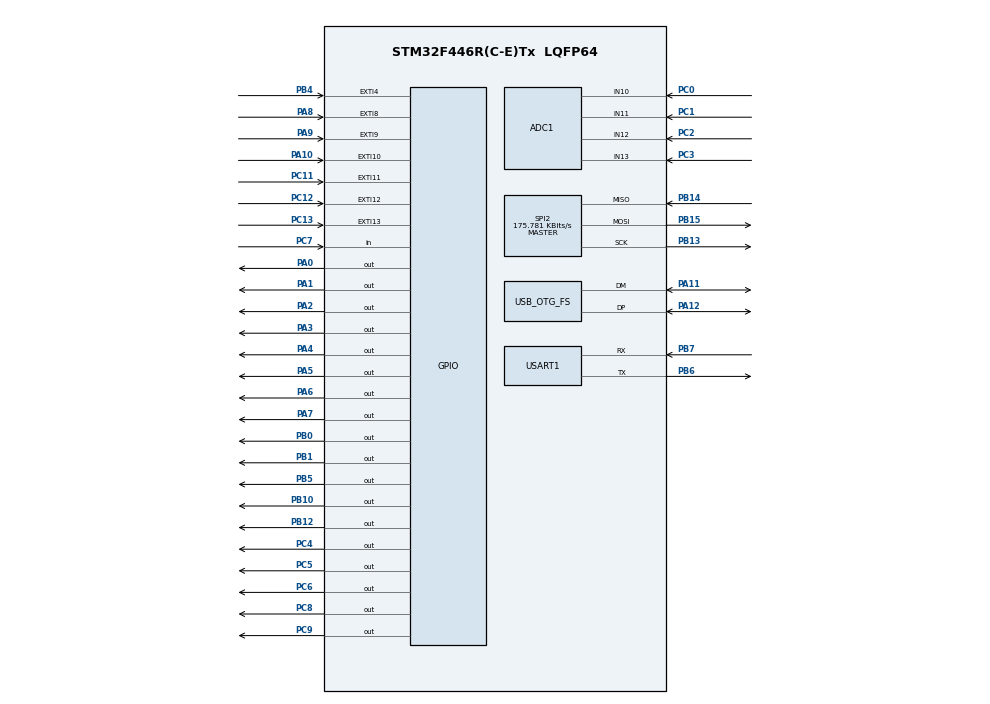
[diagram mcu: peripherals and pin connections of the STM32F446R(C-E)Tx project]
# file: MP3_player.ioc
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ADC1.Channel-0\#ChannelRegularConversion=ADC_CHANNEL_10
ADC1.NbrOfConversionFlag=1
ADC1.Rank-0\#ChannelRegularConversion=1
ADC1.SamplingTime-0\#ChannelRegularConversion=ADC_SAMPLETIME_3CYCLES
ADC1.master=1
FATFS._USE_FIND=1
FATFS._USE_LFN=2
FREERTOS.Tasks01=ControlTask,24,128,StartControlTask,Default,NULL,Dynamic,NULL,NULL;AudioTask,8,512,StartAudioTask,Default,NULL,Dynamic,NULL,NULL
FREERTOS.configUSE_NEWLIB_REENTRANT=1
Mcu.Family=STM32F4
Mcu.Name=STM32F446R(C-E)Tx
Mcu.Package=LQFP64
NVIC.EXTI15_10_IRQn=true\:5\:0\:false\:false\:true\:true\:true\:true\:true
NVIC.EXTI4_IRQn=true\:5\:0\:false\:false\:true\:true\:true\:true\:true
NVIC.EXTI9_5_IRQn=true\:5\:0\:false\:false\:true\:true\:true\:true\:true
NVIC.PriorityGroup=NVIC_PRIORITYGROUP_4
NVIC.TIM6_DAC_IRQn=true\:15\:0\:false\:false\:true\:false\:false\:true\:true
NVIC.TimeBase=TIM6_DAC_IRQn
NVIC.TimeBaseIP=TIM6
PA0-WKUP.Signal=GPIO_Output
PA1.Signal=GPIO_Output
PA10.Signal=GPXTI10
PA11.Mode=Device_Only
PA11.Signal=USB_OTG_FS_DM
PA12.Mode=Device_Only
PA12.Signal=USB_OTG_FS_DP
PA13.Mode=Serial_Wire
PA13.Signal=SYS_JTMS-SWDIO
PA14.Mode=Serial_Wire
PA14.Signal=SYS_JTCK-SWCLK
PA2.Signal=GPIO_Output
PA3.Signal=GPIO_Output
PA4.Signal=GPIO_Output
PA5.Signal=GPIO_Output
PA6.Signal=GPIO_Output
PA7.Signal=GPIO_Output
PA8.Signal=GPXTI8
PA9.Signal=GPXTI9
PB0.Signal=GPIO_Output
PB1.Signal=GPIO_Output
PB10.Signal=GPIO_Output
PB12.Signal=GPIO_Output
PB13.Mode=Full_Duplex_Master
PB13.Signal=SPI2_SCK
PB14.Mode=Full_Duplex_Master
PB14.Signal=SPI2_MISO
PB15.Mode=Full_Duplex_Master
PB15.Signal=SPI2_MOSI
PB4.Signal=GPXTI4
PB5.Signal=GPIO_Output
PB6.Mode=Asynchronous
PB6.Signal=USART1_TX
PB7.Mode=Asynchronous
PB7.Signal=USART1_RX
PC0.Signal=ADCx_IN10
PC1.Signal=ADCx_IN11
PC11.Signal=GPXTI11
PC12.Signal=GPXTI12
PC13.Signal=GPXTI13
PC14-OSC32_IN.Mode=LSE-External-Oscillator
PC14-OSC32_IN.Signal=RCC_OSC32_IN
PC15-OSC32_OUT.Mode=LSE-External-Oscillator
PC15-OSC32_OUT.Signal=RCC_OSC32_OUT
PC2.Signal=ADCx_IN12
PC3.Signal=ADCx_IN13
PC4.Signal=GPIO_Output
PC5.Signal=GPIO_Output
PC6.Signal=GPIO_Output
PC7.Signal=GPIO_Input
PC8.Signal=GPIO_Output
PC9.Signal=GPIO_Output
PH0-OSC_IN.Mode=HSE-External-Oscillator
PH0-OSC_IN.Signal=RCC_OSC_IN
PH1-OSC_OUT.Mode=HSE-External-Oscillator
PH1-OSC_OUT.Signal=RCC_OSC_OUT
ProjectManager.HeapSize=0x200
ProjectManager.StackSize=0x400
ProjectManager.TargetToolchain=STM32CubeIDE
RCC.AHBFreq_Value=90000000
RCC.APB1CLKDivider=RCC_HCLK_DIV2
RCC.APB1Freq_Value=45000000
RCC.APB1TimFreq_Value=90000000
RCC.APB2Freq_Value=90000000
RCC.APB2TimFreq_Value=90000000
RCC.CortexFreq_Value=90000000
RCC.HCLKFreq_Value=90000000
RCC.HSE_VALUE=8000000
RCC.PLLM=8
RCC.PLLN=360
RCC.PLLP=RCC_PLLP_DIV4
RCC.PLLSAIM=8
RCC.PLLSAIP=RCC_PLLSAIP_DIV4
RCC.PLLSourceVirtual=RCC_PLLSOURCE_HSE
RCC.SYSCLKFreq_VALUE=90000000
RCC.SYSCLKSource=RCC_SYSCLKSOURCE_PLLCLK
RCC.USBCLockSelection=RCC_CLK48CLKSOURCE_PLLSAIP
RCC.USBFreq_Value=48000000
RCC.VCOOutputFreq_Value=360000000
SH.ADCx_IN10.0=ADC1_IN10,IN10
SH.ADCx_IN11.0=ADC1_IN11,IN11
SH.ADCx_IN12.0=ADC1_IN12,IN12
SH.ADCx_IN13.0=ADC1_IN13,IN13
SPI2.BaudRatePrescaler=SPI_BAUDRATEPRESCALER_256
SPI2.CalculateBaudRate=175.781 KBits/s
SPI2.Direction=SPI_DIRECTION_2LINES
SPI2.Mode=SPI_MODE_MASTER
SPI2.VirtualType=VM_MASTER
USART1.VirtualMode=VM_ASYNC
USB_OTG_FS.VirtualMode=Device_Only
VP_FATFS_VS_Generic.Mode=User_defined
VP_FREERTOS_VS_CMSIS_V2.Mode=CMSIS_V2
VP_SYS_VS_tim6.Mode=TIM6
board=custom

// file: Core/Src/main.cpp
/* USER CODE BEGIN Header */
/**
 ******************************************************************************
 * @file           : main.c
 * @brief          : Main program body
 ******************************************************************************
 * @attention
 *
 * Copyright (c) 2025 STMicroelectronics.
 * All rights reserved.
 *
 * This software is licensed under terms that can be found in the LICENSE file
 * in the root directory of this software component.
 * If no LICENSE file comes with this software, it is provided AS-IS.
 *
 ******************************************************************************
 */
/* USER CODE END Header */
#include "main.h"
#include <cstdio>
#include <iostream>

#include "cmsis_os.h"
#include "fatfs.h"
//#include "lvgl.h"

#include "myfunc.h"
#include "MP3.h"
#include "Bitmap.h"

#include "TFT_LCD.h"
#include "SDcard.h"
#include "VS1003B.h"

using namespace std;

ADC_HandleTypeDef hadc1;

SPI_HandleTypeDef hspi2;

UART_HandleTypeDef huart1;

PCD_HandleTypeDef hpcd_USB_OTG_FS;

/* Definitions for ControlTask */
osThreadId_t ControlTaskHandle;
const osThreadAttr_t ControlTask_attributes = { .name = "ControlTask",
		.stack_size = 1024 * 4, .priority = (osPriority_t) osPriorityNormal, };
/* Definitions for AudioTask */
osThreadId_t AudioTaskHandle;
const osThreadAttr_t AudioTask_attributes = { .name = "AudioTask", .stack_size =
		1024 * 4, .priority = (osPriority_t) osPriorityLow, };

osSemaphoreId_t stateSemaphore;
osMessageQueueId_t buttonQueue;

/*class UARTRedirector: public std::streambuf {
protected:
	int overflow(int c) override {
		if (c != EOF) {
			HAL_UART_Transmit(&huart1, (uint8_t*) &c, 1, HAL_MAX_DELAY);
		}
		return c;
	}
};*/
class UARTRedirector : public std::streambuf {
private:
  char buffer[128];
  int pos = 0;
protected:
  int overflow(int c) override {
    if (c != EOF) {
      buffer[pos++] = (char)c;
      if (pos >= sizeof(buffer) || c == '\n') {
        HAL_UART_Transmit(&huart1, (uint8_t*)buffer, pos, 10);
        pos = 0;
      }
    }
    return c;
  }
  int sync() override {
    if (pos > 0) {
      HAL_UART_Transmit(&huart1, (uint8_t*)buffer, pos, 10);
      pos = 0;
    }
    return 0;
  }
};

UARTRedirector uart_redirector;

void SystemClock_Config(void);
static void MX_GPIO_Init(void);
static void MX_ADC1_Init(void);
static void MX_SPI2_Init(void);
static void MX_USART1_UART_Init(void);
static void MX_USB_OTG_FS_PCD_Init(void);
void StartControlTask(void *argument);
void StartAudioTask(void *argument);

void Home_page();
static void Main_page();
static void init_page();
void UpdateMusicName(char* name);
void FolderListPage(TCHAR* PATH);

/* USER CODE BEGIN 0 */

TFT_LCD &lcd = TFT_LCD::getInstance();
SDcard &sd = SDcard::getInstance();
VS1003B &vs = VS1003B::getInstance();
char PATH[256]="/";
int current_page=HOME_PAGE;
bool botton_next = 0;
bool botton_prev = 0;
bool botton_repeat = 0;
bool botton_pause = 0;
bool init=0;
volatile bool is_playing = 0;
bool reset_track = 1;
volatile int numofFile = 0;
int music_no = 0;
uint8_t volume=200;
int FolderCount=0;
int folders=0;
uint8_t folder_idx=0;
#define SIZE 100

uint16_t play_emoji[SIZE * SIZE];
uint16_t pause_emoji[SIZE * SIZE];
//uint16_t next_emoji[SIZE * SIZE];
uint16_t prev_emoji[SIZE * SIZE];
uint16_t repeat[3200];
uint16_t repeat1[3200];

extern FATFS fs;           // File system object
extern FIL fil;            // File object
extern FILINFO fno;        // File information object
extern DIR dir;            // Directory object
extern TCHAR fileNames[MAX_FILES][MAX_FILENAME];  // 파일 이름 저장 배열
extern TCHAR FolderNames[MAX_FILES][MAX_FILENAME];
extern volatile UINT fileCount; // 파일 개수

/* USER CODE END 0 */

int main(void) {

	/* MCU Configuration--------------------------------------------------------*/

	/* Reset of all peripherals, Initializes the Flash interface and the Systick. */
	HAL_Init();

	/* Configure the system clock */
	SystemClock_Config();

	/* Initialize all configured peripherals */
	MX_GPIO_Init();
	MX_ADC1_Init();
	MX_SPI2_Init();
	MX_USART1_UART_Init();
	//MX_USB_OTG_FS_PCD_Init();
	MX_FATFS_Init();
	std::cout.rdbuf(&uart_redirector);
	/* USER CODE BEGIN 2 */
	//init_page();
	//cout<<"music start\r"<<endl;
	//MP3_Play(0);
	//cout<<"kernel start\r"<<endl;
	/* USER CODE END 2 */

	/* Init scheduler */
	osKernelInitialize();

	/* USER CODE BEGIN RTOS_SEMAPHORES */
	stateSemaphore = osSemaphoreNew(1, 1, NULL);
	if (stateSemaphore == NULL) {
		cout<<"Failed to create stateSemaphore\r\n";
	}
	/* USER CODE END RTOS_SEMAPHORES */

	/* USER CODE BEGIN RTOS_QUEUES */
	/* add queues, ... */
	buttonQueue = osMessageQueueNew(10, sizeof(uint8_t), NULL); // 큐 생성
	if (buttonQueue == NULL) {
		cout<<"Failed to create buttonQueue\r\n";
	}
	/* USER CODE END RTOS_QUEUES */

	/* Create the thread(s) */
	/* creation of ControlTask */
	ControlTaskHandle = osThreadNew(StartControlTask, NULL,	&ControlTask_attributes);

	/* creation of AudioTask */
	AudioTaskHandle = osThreadNew(StartAudioTask, NULL, &AudioTask_attributes);

	/* Start scheduler */
	osKernelStart();

	/* We should never get here as control is now taken by the scheduler */

	/* Infinite loop */
	while (1) {

	}
}

static void init_page() {

	lcd.init();  //8bit
	//lcd.init(&hspi2);
	lcd.color_screen_8(Black);

	//cout << "lcd init\r" << endl;
	//printf("finished/n/r");
	HAL_GPIO_WritePin(TFT_CS_PORT, TFT_CS, GPIO_PIN_SET);
	HAL_GPIO_WritePin(vs1003_PORT, VS1003B_XCS, GPIO_PIN_SET);
	HAL_GPIO_WritePin(vs1003_PORT, VS1003B_XDCS, GPIO_PIN_SET);
	HAL_GPIO_WritePin(SD_PORT, SD_CS, GPIO_PIN_SET);
	HAL_GPIO_WritePin(SD_PORT, EXT_SD_CS, GPIO_PIN_SET);
	HAL_GPIO_WritePin(SD_PORT, EXT2_SD_CS, GPIO_PIN_SET);

	if (sd.SD_Init(&hspi2))
	{
		std::cout << "sd card failed\r" << std::endl;
		lcd.string(40,150,White,Black,"SD card init failed");
		lcd.string(40,180,White,Black,"Check the SD card");
	}
	else
		std::cout << "sd card success\r" << std::endl;

	sd.FAT_Init();
	vs.vs1003b_init(&hspi2);
	sd.SPI_speed_11MHz();
	numofFile = sd.fatGetDirEntry();
	//cout << "num of File=" << std::dec << numofFile << "\r" << endl;

	//char buffer[20];

	//snprintf(buffer, sizeof(buffer), "%d", numofFile);

	//if(DEBUG) lcd.string(10, 340, Cyan, Black, "num of files:");
	//if(DEBUG) lcd.string(120, 340, Cyan, Black, buffer);

	if (f_mount(&fs, "", 1) == FR_OK)
	{
		std::cout << "Filesystem mounted!\r" << std::endl;
		display_bmp_to_lcd(90,120,"Logo.bmp");
		display_bmp_to_lcd(30,300,"product_name.bmp");

		lcd.string(40,390,White,Black,"Resource loading...");
		display_bmp_to_arr("play.bmp",play_emoji);
		//display_bmp_to_arr("next.bmp",next_emoji);
		display_bmp_to_arr("prev.bmp",prev_emoji);
		display_bmp_to_arr("pause.bmp",pause_emoji);
		display_bmp_to_arr("repeat.bmp",repeat);
		display_bmp_to_arr("repeat1.bmp",repeat1);
		//display_bmp_to_arr("start.bmp",start_logo);
		lcd.string(40,390,White,Black,"Resource loading... Done");

	} else {
		std::cout << "Filesystem mount failed!\r" << std::endl;
	}

}

static void Main_page() {
	lcd.color_screen_8(Background_gray);
	lcd.Rectangle(Rect(0, 0, TFTWIDTH-1, 50), 2, White);
	lcd.frame();
	//lcd.Circle(160,160,10,White);
	lcd.string_size(20, 20, White, button_gray, "Play", 2, 2);
	lcd.string_size(10, 70, White, Background_gray, "Playing", 2, 2);
	lcd.string_size(10, 270, White, Background_gray, "Now:", 2, 2);
	lcd.bitmap(prev_emoji,10,370,100,100);
	lcd.bitmap(play_emoji,110,370,100,100);
	lcd.bitmap_b(prev_emoji,210,370,100,100);
	//lcd.bitmap(next_emoji,210,370,100,100);
	lcd.bitmap(repeat,10,330,80,40);
	display_bmp_to_lcd(0,90,"album.bmp");
//	f_mount(NULL,"",0);
//	f_mount(&fs,"",1);
//	f_chdir(PATH);
	lcd.frame();
//	display_bmp_to_lcd( 110, 370, "play.bmp");
//	cout<<"lcd_finish\r\n";

}

void Home_page()
{
	strcpy(PATH,"/");
	f_chdir(PATH);
	lcd.color_screen_8(Black);
	display_bmp_to_lcd(60,190,"start.bmp");
	f_mount(NULL,"",0);
	f_mount(&fs,"",1);

}
void FolderListPage(TCHAR* PATH)
{
	lcd.color_screen_8(Black);
	lcd.Rectangle(Rect(0, 0, TFTWIDTH-1, 30), 2, White);
	lcd.frame();
	FolderCount=ScanFolder(PATH);
	if(FolderCount>0)
	{
		lcd.string_size(15, 5, White, Black, "Select a Folder", 1, 1);
		for(int i=1;i<=FolderCount;i++)
		{
			lcd.string_size(30, LISTBOX_HEIGHT*i, White, Black, FolderNames[i-1], 1, 1);
		}
		lcd.Circle(15, LISTBOX_HEIGHT, 7, White, 1);
	}
	else
	{
		lcd.string_size(30, 200, White, Black, "There is no Folders", 1, 1);
	}

}
void UpdateMusicName(char* name)
{
	lcd.Block(Rect(5,290,310,30), Background_gray, Background_gray);
	lcd.string_size(20, 290, White, Background_gray, name, 1, 1);
}

void SystemClock_Config(void) {
	RCC_OscInitTypeDef RCC_OscInitStruct = { 0 };
	RCC_ClkInitTypeDef RCC_ClkInitStruct = { 0 };

	/** Configure the main internal regulator output voltage
	 */
	__HAL_RCC_PWR_CLK_ENABLE();
	__HAL_PWR_VOLTAGESCALING_CONFIG(PWR_REGULATOR_VOLTAGE_SCALE1);//3

	/** Initializes the RCC Oscillators according to the specified parameters
	 * in the RCC_OscInitTypeDef structure.
	 */
	RCC_OscInitStruct.OscillatorType = RCC_OSCILLATORTYPE_HSE;
	RCC_OscInitStruct.HSEState = RCC_HSE_ON;
	RCC_OscInitStruct.PLL.PLLState = RCC_PLL_ON;
	RCC_OscInitStruct.PLL.PLLSource = RCC_PLLSOURCE_HSE;
	RCC_OscInitStruct.PLL.PLLM = 8;
	RCC_OscInitStruct.PLL.PLLN = 360;
	RCC_OscInitStruct.PLL.PLLP = RCC_PLLP_DIV2;
	RCC_OscInitStruct.PLL.PLLQ = 2;
	RCC_OscInitStruct.PLL.PLLR = 2;
	if (HAL_RCC_OscConfig(&RCC_OscInitStruct) != HAL_OK) {
		Error_Handler();
	}

	/** Activate the Over-Drive mode
		 */
		if (HAL_PWREx_EnableOverDrive() != HAL_OK) {
			Error_Handler();
		}

	/** Initializes the CPU, AHB and APB buses clocks
	 */
	RCC_ClkInitStruct.ClockType = RCC_CLOCKTYPE_HCLK | RCC_CLOCKTYPE_SYSCLK
			| RCC_CLOCKTYPE_PCLK1 | RCC_CLOCKTYPE_PCLK2;
	RCC_ClkInitStruct.SYSCLKSource = RCC_SYSCLKSOURCE_PLLCLK;
	RCC_ClkInitStruct.AHBCLKDivider = RCC_SYSCLK_DIV2;
	RCC_ClkInitStruct.APB1CLKDivider = RCC_HCLK_DIV2;
	RCC_ClkInitStruct.APB2CLKDivider = RCC_HCLK_DIV1;

	if (HAL_RCC_ClockConfig(&RCC_ClkInitStruct, FLASH_LATENCY_2) != HAL_OK) {
		Error_Handler();
	}
}

static void MX_ADC1_Init(void) {

	ADC_ChannelConfTypeDef sConfig = { 0 };

	/** Configure the global features of the ADC (Clock, Resolution, Data Alignment and number of conversion)
	 */
	hadc1.Instance = ADC1;
	hadc1.Init.ClockPrescaler = ADC_CLOCK_SYNC_PCLK_DIV4;
	hadc1.Init.Resolution = ADC_RESOLUTION_12B;
	hadc1.Init.ScanConvMode = DISABLE;
	hadc1.Init.ContinuousConvMode = DISABLE;
	hadc1.Init.DiscontinuousConvMode = DISABLE;
	hadc1.Init.ExternalTrigConvEdge = ADC_EXTERNALTRIGCONVEDGE_NONE;
	hadc1.Init.ExternalTrigConv = ADC_SOFTWARE_START;
	hadc1.Init.DataAlign = ADC_DATAALIGN_RIGHT;
	hadc1.Init.NbrOfConversion = 1;
	hadc1.Init.DMAContinuousRequests = DISABLE;
	hadc1.Init.EOCSelection = ADC_EOC_SINGLE_CONV;
	if (HAL_ADC_Init(&hadc1) != HAL_OK) {
		Error_Handler();
	}

	/** Configure for the selected ADC regular channel its corresponding rank in the sequencer and its sample time.
	 */
	sConfig.Channel = ADC_CHANNEL_10;
	sConfig.Rank = 1;
	sConfig.SamplingTime = ADC_SAMPLETIME_3CYCLES;
	if (HAL_ADC_ConfigChannel(&hadc1, &sConfig) != HAL_OK) {
		Error_Handler();
	}

}

static void MX_SPI2_Init(void) {

	/* USER CODE BEGIN SPI2_Init 0 */
	__HAL_RCC_SPI2_CLK_ENABLE();
	/* USER CODE END SPI2_Init 0 */

	/* SPI2 parameter configuration*/
	hspi2.Instance = SPI2;
	hspi2.Init.Mode = SPI_MODE_MASTER;
	hspi2.Init.Direction = SPI_DIRECTION_2LINES;
	hspi2.Init.DataSize = SPI_DATASIZE_8BIT;
	hspi2.Init.CLKPolarity = SPI_POLARITY_LOW;
	hspi2.Init.CLKPhase = SPI_PHASE_1EDGE;
	hspi2.Init.NSS = SPI_NSS_SOFT;
	hspi2.Init.BaudRatePrescaler = SPI_BAUDRATEPRESCALER_4;
	hspi2.Init.FirstBit = SPI_FIRSTBIT_MSB;
	hspi2.Init.TIMode = SPI_TIMODE_DISABLE;
	hspi2.Init.CRCCalculation = SPI_CRCCALCULATION_DISABLE;
	hspi2.Init.CRCPolynomial = 10;
	if (HAL_SPI_Init(&hspi2) != HAL_OK) {
		Error_Handler();
	}

}

static void MX_USART1_UART_Init(void) {

	huart1.Instance = USART1;
	huart1.Init.BaudRate = 115200;
	huart1.Init.WordLength = UART_WORDLENGTH_8B;
	huart1.Init.StopBits = UART_STOPBITS_1;
	huart1.Init.Parity = UART_PARITY_NONE;
	huart1.Init.Mode = UART_MODE_TX_RX;
	huart1.Init.HwFlowCtl = UART_HWCONTROL_NONE;
	huart1.Init.OverSampling = UART_OVERSAMPLING_16;
	if (HAL_UART_Init(&huart1) != HAL_OK) {
		Error_Handler();
	}

}

static void MX_USB_OTG_FS_PCD_Init(void) {

	hpcd_USB_OTG_FS.Instance = USB_OTG_FS;
	hpcd_USB_OTG_FS.Init.dev_endpoints = 6;
	hpcd_USB_OTG_FS.Init.speed = PCD_SPEED_FULL;
	hpcd_USB_OTG_FS.Init.dma_enable = DISABLE;
	hpcd_USB_OTG_FS.Init.phy_itface = PCD_PHY_EMBEDDED;
	hpcd_USB_OTG_FS.Init.Sof_enable = DISABLE;
	hpcd_USB_OTG_FS.Init.low_power_enable = DISABLE;
	hpcd_USB_OTG_FS.Init.lpm_enable = DISABLE;
	hpcd_USB_OTG_FS.Init.vbus_sensing_enable = DISABLE;
	hpcd_USB_OTG_FS.Init.use_dedicated_ep1 = DISABLE;
	if (HAL_PCD_Init(&hpcd_USB_OTG_FS) != HAL_OK) {
		Error_Handler();
	}

}

static void MX_GPIO_Init(void) {
	GPIO_InitTypeDef GPIO_InitStruct = { 0 };

	/* GPIO Ports Clock Enable */
	__HAL_RCC_GPIOC_CLK_ENABLE();
	__HAL_RCC_GPIOH_CLK_ENABLE();
	__HAL_RCC_GPIOA_CLK_ENABLE();
	__HAL_RCC_GPIOB_CLK_ENABLE();

	/*Configure GPIO pin Output Level */
	HAL_GPIO_WritePin(GPIOA,
			GPIO_PIN_0 | GPIO_PIN_1 | GPIO_PIN_2 | GPIO_PIN_3 | GPIO_PIN_4
					| GPIO_PIN_5 | GPIO_PIN_6 | GPIO_PIN_7, GPIO_PIN_RESET);

	/*Configure GPIO pin Output Level */
	HAL_GPIO_WritePin(GPIOC,
			GPIO_PIN_4 | GPIO_PIN_5 | GPIO_PIN_6 | GPIO_PIN_8 | GPIO_PIN_9
					| BOTTON_REPEAT | BOTTON_VOL_P | BOTTON_VOL_M, GPIO_PIN_RESET);

	/*Configure GPIO pin Output Level */
	HAL_GPIO_WritePin(GPIOB,
	GPIO_PIN_0 | GPIO_PIN_1 | BOTTON_HOME| GPIO_PIN_10 | GPIO_PIN_12 | GPIO_PIN_5,
			GPIO_PIN_RESET);

	HAL_GPIO_WritePin(GPIOB, SCK2 | MISO2 | MOSI2, GPIO_PIN_RESET);

	HAL_GPIO_WritePin(vs1003_PORT, VS1003B_XDCS, GPIO_PIN_RESET);
	HAL_GPIO_WritePin(vs1003_PORT, VS1003B_XCS, GPIO_PIN_RESET);
	HAL_GPIO_WritePin(SD_PORT, SD_CS, GPIO_PIN_RESET);
	HAL_GPIO_WritePin(SD_PORT, EXT_SD_CS, GPIO_PIN_RESET);
	HAL_GPIO_WritePin(SD_PORT, EXT2_SD_CS, GPIO_PIN_RESET);
	/*Configure GPIO pins : PC13 PC11 PC12 */
	GPIO_InitStruct.Pin = BOTTON_REPEAT | BOTTON_VOL_P | BOTTON_VOL_M;
	GPIO_InitStruct.Mode = GPIO_MODE_IT_RISING;
	GPIO_InitStruct.Pull = GPIO_NOPULL;
	HAL_GPIO_Init(GPIOC, &GPIO_InitStruct);

	/*Configure GPIO pin : PB4 */
	GPIO_InitStruct = { 0 };
	GPIO_InitStruct.Pin = BOTTON_HOME;
	GPIO_InitStruct.Mode = GPIO_MODE_IT_RISING;
	GPIO_InitStruct.Pull = GPIO_NOPULL;
	HAL_GPIO_Init(GPIOB, &GPIO_InitStruct);

	/*Configure GPIO pins : PA8 PA9 PA10 */
	GPIO_InitStruct = { 0 };
	GPIO_InitStruct.Pin = BOTTON_NEXT | BOTTON_PAUSE | BOTTON_PREV;
	GPIO_InitStruct.Mode = GPIO_MODE_IT_RISING;
	GPIO_InitStruct.Pull = GPIO_NOPULL;
	HAL_GPIO_Init(GPIOA, &GPIO_InitStruct);

	/*Configure GPIO pins : PA0 PA1 PA2 PA3
	 PA4 PA5 PA6 PA7 */
	GPIO_InitStruct = { 0 };
	GPIO_InitStruct.Pin = GPIO_PIN_0 | GPIO_PIN_1 | GPIO_PIN_2 | GPIO_PIN_3
			| GPIO_PIN_4 | GPIO_PIN_5 | GPIO_PIN_6 | GPIO_PIN_7;
	GPIO_InitStruct.Mode = GPIO_MODE_OUTPUT_PP;
	GPIO_InitStruct.Pull = GPIO_NOPULL;
	GPIO_InitStruct.Speed = GPIO_SPEED_FREQ_VERY_HIGH;
	HAL_GPIO_Init(GPIOA, &GPIO_InitStruct);

	/*Configure GPIO pins : PC4 PC5 PC6 PC8
	 PC9 */
	GPIO_InitStruct = { 0 };
	GPIO_InitStruct.Pin = GPIO_PIN_4 | GPIO_PIN_5 | GPIO_PIN_6 | GPIO_PIN_8
			| GPIO_PIN_9;
	GPIO_InitStruct.Mode = GPIO_MODE_OUTPUT_PP;
	GPIO_InitStruct.Pull = GPIO_NOPULL;
	GPIO_InitStruct.Speed = GPIO_SPEED_FREQ_VERY_HIGH;
	HAL_GPIO_Init(GPIOC, &GPIO_InitStruct);

	/*Configure GPIO pins : PB0 PB1 PB10 PB12
	 PB5 */
	GPIO_InitStruct = { 0 };
	GPIO_InitStruct.Pin = GPIO_PIN_0 | GPIO_PIN_1 | GPIO_PIN_10 | GPIO_PIN_12
			| GPIO_PIN_5;
	GPIO_InitStruct.Mode = GPIO_MODE_OUTPUT_PP;
	GPIO_InitStruct.Pull = GPIO_NOPULL;
	GPIO_InitStruct.Speed = GPIO_SPEED_FREQ_VERY_HIGH;
	HAL_GPIO_Init(GPIOB, &GPIO_InitStruct);

	GPIO_InitStruct = { 0 };
	GPIO_InitStruct.Pin = EXT_SD_CS | SD_CS | EXT2_SD_CS;
	GPIO_InitStruct.Mode = GPIO_MODE_OUTPUT_PP;
	GPIO_InitStruct.Pull = GPIO_NOPULL;    //GPIO_PULLUP
	GPIO_InitStruct.Speed = GPIO_SPEED_FREQ_VERY_HIGH;
	HAL_GPIO_Init(GPIOB, &GPIO_InitStruct);
	/*Configure GPIO pin : PC7 */
	GPIO_InitStruct = { 0 };
	GPIO_InitStruct.Pin = GPIO_PIN_7;
	GPIO_InitStruct.Mode = GPIO_MODE_INPUT;
	GPIO_InitStruct.Pull = GPIO_NOPULL;
	HAL_GPIO_Init(GPIOC, &GPIO_InitStruct);

	GPIO_InitStruct = { 0 };
	GPIO_InitStruct.Pin = SCK2;
	GPIO_InitStruct.Mode = GPIO_MODE_AF_PP; // Alternate Function Push Pull
	GPIO_InitStruct.Pull = GPIO_NOPULL;    // Pull-Up/Down 없음
	GPIO_InitStruct.Speed = GPIO_SPEED_FREQ_VERY_HIGH; // 속도 설정
	GPIO_InitStruct.Alternate = GPIO_AF5_SPI2; // Alternate Function 번호
	HAL_GPIO_Init(SPI_PORT, &GPIO_InitStruct);

	GPIO_InitStruct = { 0 };
	GPIO_InitStruct.Pin = MISO2 | MOSI2;
	GPIO_InitStruct.Mode = GPIO_MODE_AF_PP; // Alternate Function Push Pull
	GPIO_InitStruct.Pull = GPIO_NOPULL;    // Pull-Up/Down 없음
	GPIO_InitStruct.Speed = GPIO_SPEED_FREQ_VERY_HIGH; // 속도 설정
	GPIO_InitStruct.Alternate = GPIO_AF5_SPI2; // Alternate Function 번호
	HAL_GPIO_Init(SPI_PORT, &GPIO_InitStruct);

	/* USER CODE BEGIN MX_GPIO_Init_2 */
	HAL_GPIO_WritePin(TFT_CS_PORT, TFT_CS, GPIO_PIN_SET);
	HAL_GPIO_WritePin(vs1003_PORT, VS1003B_XDCS, GPIO_PIN_SET);
	HAL_GPIO_WritePin(vs1003_PORT, VS1003B_XCS, GPIO_PIN_SET);
	HAL_GPIO_WritePin(SD_PORT, SD_CS, GPIO_PIN_SET);
	HAL_GPIO_WritePin(SD_PORT, EXT_SD_CS, GPIO_PIN_SET);
	HAL_GPIO_WritePin(SD_PORT, EXT2_SD_CS, GPIO_PIN_SET);

	/* EXTI interrupt init*/
	  HAL_NVIC_SetPriority(EXTI4_IRQn, 5, 0);
	  HAL_NVIC_EnableIRQ(EXTI4_IRQn);

	  HAL_NVIC_SetPriority(EXTI9_5_IRQn, 5, 0);
	  HAL_NVIC_EnableIRQ(EXTI9_5_IRQn);

	  HAL_NVIC_SetPriority(EXTI15_10_IRQn, 5, 0);
	  HAL_NVIC_EnableIRQ(EXTI15_10_IRQn);
	/* USER CODE BEGIN MX_GPIO_Init_2 */
	/* USER CODE END MX_GPIO_Init_2 */
}

//USER CODE BEGIN 4
void EXTI4_IRQHandler(void) {
	HAL_GPIO_EXTI_IRQHandler(BOTTON_HOME); //
}
void EXTI8_IRQHandler(void) {
	HAL_GPIO_EXTI_IRQHandler(BOTTON_NEXT); //
}
void EXTI9_IRQHandler(void) {
	HAL_GPIO_EXTI_IRQHandler(BOTTON_PAUSE); //
}
void EXTI10_IRQHandler(void) {
	HAL_GPIO_EXTI_IRQHandler(BOTTON_PREV); //
}
void EXTI11_IRQHandler(void) {
	HAL_GPIO_EXTI_IRQHandler(BOTTON_VOL_P); //
}
void EXTI12_IRQHandler(void) {
	HAL_GPIO_EXTI_IRQHandler(BOTTON_VOL_M); //
}
void EXTI13_IRQHandler(void) {
	HAL_GPIO_EXTI_IRQHandler(BOTTON_REPEAT); //
}

void HAL_GPIO_EXTI_Callback(uint16_t GPIO_Pin) {
	BaseType_t xHigherPriorityTaskWoken = pdFALSE;
	int event=0;
	if (GPIO_Pin == BOTTON_VOL_P) { // 버튼 핀 확인
		event = EVENT_VOL_P;
	}
	else if (GPIO_Pin == BOTTON_VOL_M) { // 버튼 핀 확인
		event = EVENT_VOL_M;
	}
	else if (GPIO_Pin == BOTTON_REPEAT) { // 버튼 핀 확인
		event = EVENT_REPEAT;
	}
	else if (GPIO_Pin == BOTTON_HOME) { // 버튼 핀 확인
		event = EVENT_HOME;
	}
	else if (GPIO_Pin == BOTTON_PAUSE) { // 버튼 핀 확인
		event = EVENT_PAUSE;
	}
	else if (GPIO_Pin == BOTTON_NEXT) { // 버튼 핀 확인
		event = EVENT_NEXT;
	}
	else if (GPIO_Pin == BOTTON_PREV) { // 버튼 핀 확인
		event = EVENT_PREV;
	}

	if(event!=0)
	{
		xTaskNotifyFromISR((TaskHandle_t)ControlTaskHandle, event, eSetValueWithOverwrite, &xHigherPriorityTaskWoken);
		portYIELD_FROM_ISR(xHigherPriorityTaskWoken); // 태스크 전환 요청
	}
}

/* USER CODE END 4 */

void StartControlTask(void *argument) {
	/* USER CODE BEGIN 5 */
	/* Infinite loop */
	uint8_t event=0;
	//current_page=PLAY_PAGE;
	is_playing = false;
	reset_track = false;
	uint32_t ulNotificationValue;
	for (;;) {
		if (xTaskNotifyWait(0x00, 0xFFFFFFFF, &ulNotificationValue,	portMAX_DELAY) == pdTRUE)
		{
			std::cout<<"botton event:"<<ulNotificationValue<<"\r"<<endl;
			osSemaphoreAcquire(stateSemaphore, osWaitForever);
			if(init){
				if (ulNotificationValue == EVENT_VOL_P)//volume up , 0 is full
				{
					if (volume < 254) volume = (254 - volume < 10) ? 250 : volume + 10;
					event=EVENT_VOL_P;
					osMessageQueuePut(buttonQueue, &event, 0, 0);
				}
				else if (ulNotificationValue == EVENT_VOL_M)//volume down, 254 is silence
				{
					if (volume > 0) volume = (volume < 10) ? 0 : volume - 10;
					event=EVENT_VOL_M;
					osMessageQueuePut(buttonQueue, &event, 0, 0);
				}

				else if(current_page == HOME_PAGE)
				{
					if (ulNotificationValue == EVENT_PAUSE)
					{
						current_page = LIST_PAGE;
						FolderListPage(PATH);
					}
				}
				else if(current_page==LIST_PAGE)
				{
					if (ulNotificationValue == EVENT_PAUSE)
					{

						append_Path(PATH,FolderNames[folder_idx]);
						// MP3 파일 검색
						scanMp3FilesSFN(PATH);
						cout<<"path:"<<PATH<<", num of Files:"<<fileCount<<"\r\n";
						//std::cout<<"num of files:"<<num<<"\r\n";
						if(fileCount>0)
						{
							f_chdir(PATH);
							std::cout << "PATH:" << PATH << "Found " << fileCount << " MP3 files:\r" << std::endl;
							for (uint16_t i = 0; i < fileCount; i++) {
								std::cout << i + 1 << ": " << fileNames[i] << "\r" << std::endl;
							}
							numofFile=fileCount;
							current_page = PLAY_PAGE;
							is_playing = true;
							reset_track = true;
							Main_page();
							event=EVENT_PAUSE;
							osMessageQueuePut(buttonQueue, &event, 0, 0);
						}
						else
						{
							strcpy(PATH,"/");
							lcd.color_screen_8(Black);
							lcd.string(100,200,White,Black,"MP3 file not detected!");
							osDelay(200);
							FolderListPage(PATH);
						}
					}
					else if (ulNotificationValue == EVENT_PREV)
					{
						lcd.Circle(15, LISTBOX_HEIGHT*(folder_idx+1), 7, Black, 1);
						folder_idx=folder_idx==0? 0:folder_idx-1;
						lcd.Circle(15, LISTBOX_HEIGHT*(folder_idx+1), 7, White, 1);
					}
					else if (ulNotificationValue == EVENT_NEXT)
					{
						lcd.Circle(15, LISTBOX_HEIGHT*(folder_idx+1), 7, Black, 1);
						folder_idx=folder_idx==FolderCount-1? folder_idx:folder_idx+1;
						lcd.Circle(15, LISTBOX_HEIGHT*(folder_idx+1), 7, White, 1);
					}

				}

				else if(current_page == PLAY_PAGE)
				{
					if (ulNotificationValue == EVENT_REPEAT)
					{ // repeat
						botton_repeat = !botton_repeat;
						if(botton_repeat) lcd.bitmap(repeat1,10,330,80,40);
						else lcd.bitmap(repeat,10,330,80,40);
					}
					if (ulNotificationValue == EVENT_HOME)
					{ // goto homepage
						current_page = HOME_PAGE;
						music_no=0;
						is_playing = false;
						reset_track = true;
						folder_idx=0;
						event=EVENT_HOME;
						osMessageQueuePut(buttonQueue, &event, 0, 0);
						//Home_page();
					}
					if (ulNotificationValue == EVENT_PAUSE)
					{ // pause/resume
						cout<<"pause pressed\r\n";
						event=EVENT_PAUSE;
						osMessageQueuePut(buttonQueue, &event, 0, 0);

						if(!is_playing)
						{
							is_playing=true;
							lcd.string_size(10, 70, White, Background_gray, "Playing", 2, 2);
							lcd.bitmap(play_emoji,110,370,100,100);
						}
						else
						{
							is_playing=false;
							lcd.string_size(10, 70, White, Background_gray, "Pause  ", 2, 2);
							lcd.bitmap(pause_emoji,110,370,100,100);
						}
						reset_track = false;
					}
					else if (ulNotificationValue == EVENT_NEXT)
					{ // next
						event=EVENT_NEXT;
						osMessageQueuePut(buttonQueue, &event, 0, 0);
					}
					else if (ulNotificationValue == EVENT_PREV)
					{ // prev
						event=EVENT_PREV;
						osMessageQueuePut(buttonQueue, &event, 0, 0);
					}
				}
			}//end of if
			osSemaphoreRelease(stateSemaphore);
		}
	}
/* USER CODE END 5 */
}
void StartAudioTask(void *argument) {
	/* USER CODE BEGIN StartAudioTask */
	u_long c_clust;
	u_long rd_sec;
	int i, n;
	u_long k = 0, kd;
    FIL fil1;
    char path[256]="/";
    FRESULT res;
	uint8_t button_event;
	bool next = 0;
	bool prev = 0;
	bool vol_change=0;
	volatile bool playing=0;
	int music;
	bool reset;
	bool repeat;
	uint8_t vol;
	UINT bytesRead;       // 읽은 바이트 수
	uint8_t buf[512];  // 데이터 버퍼 (섹터 크기 맞춤)
	init_page();
	Home_page();
	osSemaphoreAcquire(stateSemaphore, osWaitForever);
	init=1;
	osSemaphoreRelease(stateSemaphore);
	vs.vs1003b_set_volume(200, 200);
	sd.SPI_speed_6MHz();

	/* Infinite loop */
	for (;;) {

		osSemaphoreAcquire(stateSemaphore, osWaitForever);
		music = music_no;
		reset = reset_track;
		repeat = botton_repeat;
		vol= volume;
		strcpy(path,PATH);
		osSemaphoreRelease(stateSemaphore);

		next = 0;
		prev = 0;
		vol_change=0;
		if (osMessageQueueGet(buttonQueue, &button_event, NULL, 0)
				== osOK) {
			if (button_event == EVENT_NEXT)
				next = true;
			else if (button_event == EVENT_PREV)
				prev = true;
			else if((button_event==EVENT_VOL_P)||(button_event==EVENT_VOL_M))
			{
				vol_change=1;
				cout<<"volume change:"<<(int)vol<<"\r"<<endl;
			}
			else if (button_event==EVENT_PAUSE)
			{
				playing=!playing;
			}
			else if (button_event==EVENT_HOME)
			{
				playing=0;
				Home_page();
			}
		}

		if (playing && reset) { // 재생 시작 시 초기화
			if(music!=0){
				osSemaphoreAcquire(stateSemaphore, osWaitForever);
				music_no = 0;
				osSemaphoreRelease(stateSemaphore);
			}
			k = 0;
			kd = sd.file_len[0];
			c_clust = sd.fileStartClust[0];
			osSemaphoreAcquire(stateSemaphore, osWaitForever);
			reset_track = false; // 초기화 후 리셋
			osSemaphoreRelease(stateSemaphore);
#ifdef USE_FATFS_LIB
			c_clust=1;
			bytesRead=0;
			//f_close(&fil);
//			osSemaphoreAcquire(stateSemaphore, osWaitForever);
//			strcpy(path,PATH);
//			osSemaphoreRelease(stateSemaphore);
//			append_Path(path,fileNames[0]);

			 if (f_open(&fil, fileNames[0], FA_READ) != FR_OK) {
				f_mount(NULL,"",0);
				f_mount(&fs,"",1);
				osSemaphoreAcquire(stateSemaphore, osWaitForever);
				f_chdir(PATH);
				osSemaphoreRelease(stateSemaphore);
				c_clust=0;
				osSemaphoreAcquire(stateSemaphore, osWaitForever);
				music_no = 1;
				osSemaphoreRelease(stateSemaphore);
				std::cout<<"file open failed: \r\n";
			    //f_mount(NULL, "", 0); // 마운트 해제
			    //return;
			}
			UpdateMusicName(fileNames[music]);
			//lcd.string_size(20, 170, White, Background_gray, fileNames[music], 1, 1);
#endif
		}
		//std::cout<<"playing:"<<playing<<", reset:"<<reset<<", music_no:"<<music<<", clust:"<<c_clust<<", k:"<<k<<", kd:"<<kd<<" vol:"<<(int)vol<<"\r"<<endl;

		if (playing &&(c_clust == 0 || next || prev)) //end of music
		{
			if (prev) {
				if (music == 0) music = numofFile - 1;
				else music--;
				osSemaphoreAcquire(stateSemaphore, osWaitForever);
				botton_prev = 0;
				osSemaphoreRelease(stateSemaphore);
			} else if (next) {
				music++;
				osSemaphoreAcquire(stateSemaphore, osWaitForever);
				botton_next = 0;
				osSemaphoreRelease(stateSemaphore);
			} else	music = repeat ? music : music + 1;

			if (music >= numofFile)
				music = 0;
			osSemaphoreAcquire(stateSemaphore, osWaitForever);
			std::cout<<"playing:"<<playing<<"is_playing:"<<is_playing<<" c_clust:"<<c_clust<<"\r\n";
			music_no = music;
			osSemaphoreRelease(stateSemaphore);

			k = 0;
			kd = sd.file_len[music];                            // 파일 길이 섹터수
			c_clust = sd.fileStartClust[music];               // f_no 파일 시작 클러스터
#ifdef USE_FATFS_LIB
			c_clust=1;
			if(f_close(&fil)!= FR_OK) std::cout<<"file close failed:\r"<<endl;
			//f_close(&fil);
//			append_Path(path,fileNames[music]);

			if (f_open(&fil, fileNames[music], FA_READ) != FR_OK) {
				f_mount(NULL,"",0);
				f_mount(&fs,"",1);
				c_clust=0;
				osSemaphoreAcquire(stateSemaphore, osWaitForever);
				f_chdir(PATH);
				music_no = music+1;
				osSemaphoreRelease(stateSemaphore);
				std::cout<<"file open failed: \r\n";
			    //f_mount(NULL, "", 0); // 마운트 해제
			    //return;
			}
			UpdateMusicName(fileNames[music]);
			//lcd.string_size(20, 170, White, Background_gray, fileNames[music], 1, 1);
#endif
		}

		if (playing) {

#ifdef USE_FATFS_LIB

			if(f_eof(&fil))//end of file
			{
				if(f_close(&fil)!= FR_OK) std::cout<<"file close failed:\r"<<endl;
				f_mount(NULL,"",0);
				f_mount(&fs,"",1);
				osSemaphoreAcquire(stateSemaphore, osWaitForever);
				f_chdir(PATH);
				osSemaphoreRelease(stateSemaphore);
				music = repeat ? music : music + 1;
				if (music >= numofFile)	music = 0;
				osSemaphoreAcquire(stateSemaphore, osWaitForever);
				music_no = music;
				osSemaphoreRelease(stateSemaphore);
//				append_Path(PATH,fileNames[music]);
				if (f_open(&fil, fileNames[music], FA_READ) != FR_OK) {
					c_clust=0;
					osSemaphoreAcquire(stateSemaphore, osWaitForever);
					music_no = music+1;
					osSemaphoreRelease(stateSemaphore);
					std::cout<<"file open failed: \r\n";
				}
				UpdateMusicName(fileNames[music]);
				//lcd.string_size(20, 170, White, Background_gray, fileNames[music], 1, 1);

			}
			else
			{
				// read file
				res=f_read(&fil, buf, sizeof(buf), &bytesRead);
				if ( res!= FR_OK) {
					std::cout<<"read failed:"<< res<<'\r'<<endl;
					DWORD pos=f_tell(&fil);
					f_close(&fil);
					f_mount(NULL,"",0);
					f_mount(&fs,"",1);
					osSemaphoreAcquire(stateSemaphore, osWaitForever);
					f_chdir(PATH);
					osSemaphoreRelease(stateSemaphore);
//					append_Path(PATH,fileNames[music]);
					if (f_open(&fil, fileNames[music], FA_READ) != FR_OK) {
						std::cout<<"file open failed: \r\n"; }
					f_lseek(&fil,pos);
					f_read(&fil, buf, sizeof(buf), &bytesRead);
				}

				if(bytesRead > 0)// if something is read
				{
					//cout<<"sizeof buf:"<<sizeof(buf)<<", bytesRead: "<<bytesRead<<"\r\n";
					HAL_GPIO_WritePin(SD_PORT, SD_CS, GPIO_PIN_SET);
					// 읽은 데이터 처리 (예: 출력 또는 오디오 재생)
					for (UINT i = 0; i < bytesRead; i++) {
						while ((vs.vs1003b_is_busy()));
						HAL_GPIO_WritePin(vs1003_PORT, VS1003B_XDCS, GPIO_PIN_RESET);
						vs.vs1003b_spi_send(buf[i]);		// VS1033 칩으로 MP3 데이터 전송
						HAL_GPIO_WritePin(vs1003_PORT, VS1003B_XDCS, GPIO_PIN_SET);
					}
					if(vol_change) {
						vs.vs1003b_set_volume(vol,vol);
						vol_change=0;
					}

					HAL_GPIO_WritePin(SD_PORT, SD_CS, GPIO_PIN_RESET);

				}
				else// nothing read, mount again
				{
					DWORD pos=f_tell(&fil);
					f_close(&fil);
					f_mount(NULL,"",0);
					f_mount(&fs,"",1);
					osSemaphoreAcquire(stateSemaphore, osWaitForever);
					f_chdir(PATH);
					osSemaphoreRelease(stateSemaphore);
//
					if (f_open(&fil, fileNames[music], FA_READ) != FR_OK) {
						std::cout<<"file open failed: \r\n"; }
					f_lseek(&fil,pos);
				}
			}
#else
			rd_sec = sd.fatClustToSect(c_clust);    // 현재 클러스터를 섹터로 변환
			for (n = 0; n < sd.SecPerClus; n++)    // 클러스터당 섹터 수만큼 읽기
			{
				sd.SD_Read(rd_sec++);			// 섹터(512바이트) 읽기
				for (i = 0; i < 512; i++)
				{				// 읽은 데이터 VS1003칩에 출력
					uint32_t timeout = 1000;
					while (vs.vs1003b_is_busy() && timeout--) {
						osDelay(1);
					}					// VS1033 데이터수신가능 체크
					if (timeout == 0)
						break;
					//while (vs.vs1003b_is_busy());
					HAL_GPIO_WritePin(vs1003_PORT, VS1003B_XDCS, GPIO_PIN_RESET);// xDCS = low, VS1033 활성화
					vs.vs1003b_spi_send(sd.buffer[i]);	// VS1003 칩으로 MP3 데이터 전송
					HAL_GPIO_WritePin(vs1003_PORT, VS1003B_XDCS, GPIO_PIN_SET); // xDCS = high, VS1033 비활성화
					if(vol_change) {
						vs.vs1003b_set_volume(vol,vol);
						vol_change=0;
					}
				}
				if (++k >= kd)
					break;
			}
			//u_long percent=(k/kd)*300;
			//lcd.Slider(0,280,percent,Background_gray,Yellow);
			c_clust = sd.FAT_NextCluster(c_clust);    // 다음 cluster계산
#endif
		}
		//osDelay(1);
	}
/* USER CODE END StartAudioTask */
}
void HAL_TIM_PeriodElapsedCallback(TIM_HandleTypeDef *htim) {
if (htim->Instance == TIM6) {
	HAL_IncTick();
}
}

void Error_Handler(void) {
__disable_irq();
while (1) {
}
}
